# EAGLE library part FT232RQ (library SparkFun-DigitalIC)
USB to USART. Non-stock item, unproven FP for this part.

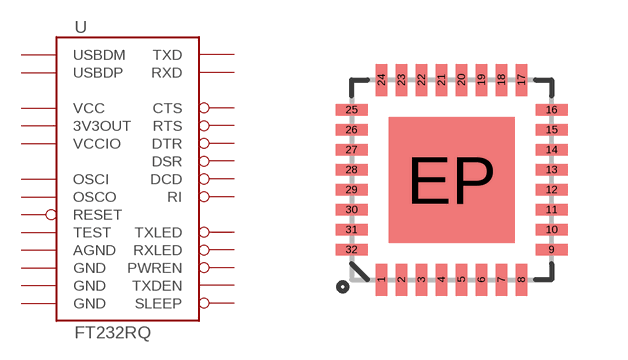
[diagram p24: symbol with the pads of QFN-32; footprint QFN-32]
Designator prefix -

## FT232RQ  [QFN-32]
1  VCCIO  pwr
2  RXD  in
3  RI  in
4  GND  pwr
6  DSR  in
7  DCD  in
8  CTS  in
9  SLEEP  in
10  TXDEN  in
11  PWREN  in
14  USBDP
15  USBDM
16  3V3OUT  out
17  GND  pwr
18  RESET  in
19  VCC  pwr
20  GND  pwr
21  RXLED  in
22  TXLED  in
24  AGND  pwr
26  TEST  in
27  OSCI  in
28  OSCO  out
30  TXD  out
31  DTR  out
32  RTS  out

## Footprint QFN-32 (pad centres in mm)
QFN 32-Pin package w/ Thermal Pad ***Unproven*** Applicable Parts: TLC5940
smd 0.285 x 0.8: 1 -1.75,-2.5; 2 -1.25,-2.5; 3 -0.75,-2.5; 4 -0.25,-2.5; 5 0.25,-2.5; 6 0.75,-2.5; 7 1.25,-2.5; 8 1.75,-2.5; 17 1.75,2.5; 18 1.25,2.5; 19 0.75,2.5; 20 0.25,2.5; 21 -0.25,2.5; 22 -0.75,2.5; 23 -1.25,2.5; 24 -1.75,2.5
smd 0.8 x 0.285: 9 2.5,-1.75; 10 2.5,-1.25; 11 2.5,-0.75; 12 2.5,-0.25; 13 2.5,0.25; 14 2.5,0.75; 15 2.5,1.25; 16 2.5,1.75; 25 -2.5,1.75; 26 -2.5,1.25; 27 -2.5,0.75; 28 -2.5,0.25; 29 -2.5,-0.25; 30 -2.5,-0.75; 31 -2.5,-1.25; 32 -2.5,-1.75
smd 3.15 x 3.15: EP 0,0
